VERSION 5.7 ;
  NOWIREEXTENSIONATPIN ON ;
  DIVIDERCHAR "/" ;
  BUSBITCHARS "[]" ;
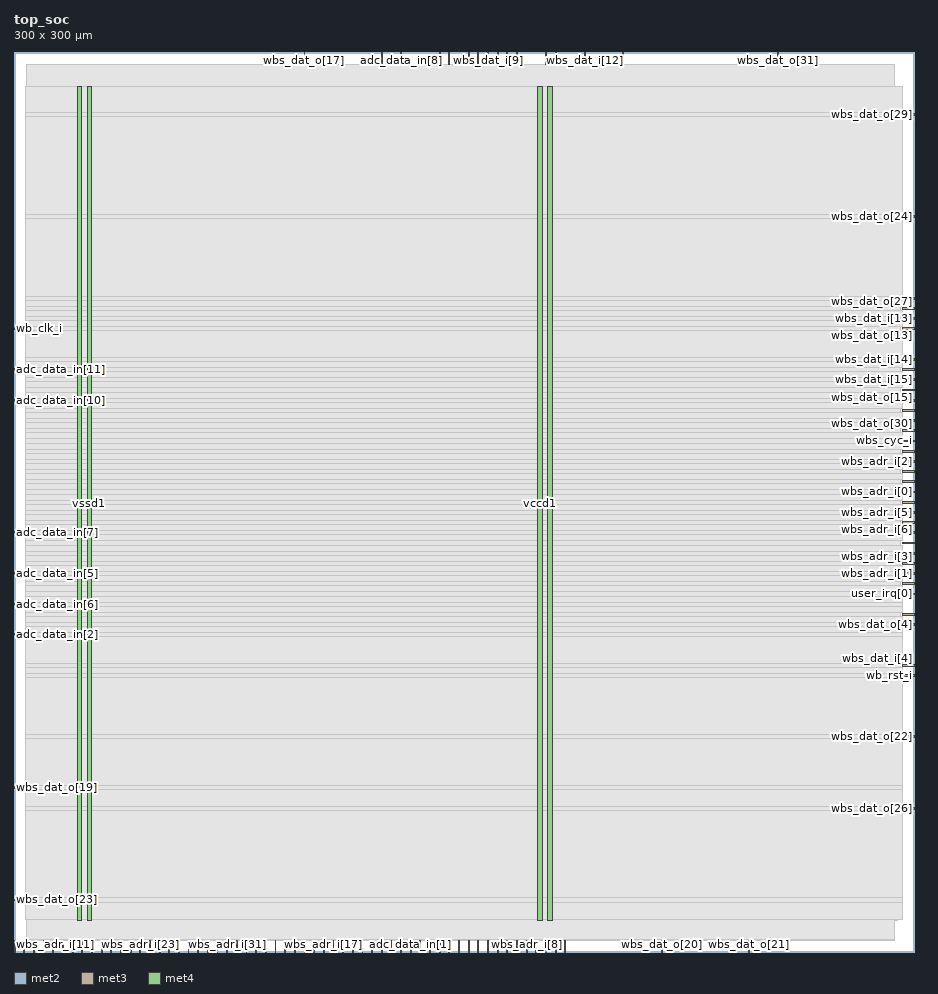
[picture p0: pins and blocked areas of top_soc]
MACRO top_soc
  CLASS BLOCK ;
  FOREIGN top_soc ;
  ORIGIN 0.000 0.000 ;
  SIZE 300.000 BY 300.000 ;
  PIN adc_data_in[0]
    DIRECTION INPUT ;
    USE SIGNAL ;
    ANTENNAGATEAREA 0.631200 ;
    ANTENNADIFFAREA 0.434700 ;
    PORT
      LAYER met2 ;
        RECT 128.890 0.000 129.170 4.000 ;
    END
  END adc_data_in[0]
  PIN adc_data_in[10]
    DIRECTION INPUT ;
    USE SIGNAL ;
    ANTENNAGATEAREA 0.631200 ;
    ANTENNADIFFAREA 0.434700 ;
    PORT
      LAYER met3 ;
        RECT 0.000 183.640 4.000 184.240 ;
    END
  END adc_data_in[10]
  PIN adc_data_in[11]
    DIRECTION INPUT ;
    USE SIGNAL ;
    ANTENNAGATEAREA 0.631200 ;
    ANTENNADIFFAREA 0.434700 ;
    PORT
      LAYER met3 ;
        RECT 0.000 193.840 4.000 194.440 ;
    END
  END adc_data_in[11]
  PIN adc_data_in[1]
    DIRECTION INPUT ;
    USE SIGNAL ;
    ANTENNAGATEAREA 0.631200 ;
    ANTENNADIFFAREA 0.434700 ;
    PORT
      LAYER met2 ;
        RECT 132.110 0.000 132.390 4.000 ;
    END
  END adc_data_in[1]
  PIN adc_data_in[2]
    DIRECTION INPUT ;
    USE SIGNAL ;
    ANTENNAGATEAREA 0.631200 ;
    ANTENNADIFFAREA 0.434700 ;
    PORT
      LAYER met3 ;
        RECT 0.000 105.440 4.000 106.040 ;
    END
  END adc_data_in[2]
  PIN adc_data_in[3]
    DIRECTION INPUT ;
    USE SIGNAL ;
    ANTENNAGATEAREA 0.631200 ;
    ANTENNADIFFAREA 0.434700 ;
    PORT
      LAYER met2 ;
        RECT 93.470 0.000 93.750 4.000 ;
    END
  END adc_data_in[3]
  PIN adc_data_in[4]
    DIRECTION INPUT ;
    USE SIGNAL ;
    ANTENNAGATEAREA 0.631200 ;
    ANTENNADIFFAREA 0.434700 ;
    PORT
      LAYER met2 ;
        RECT 135.330 0.000 135.610 4.000 ;
    END
  END adc_data_in[4]
  PIN adc_data_in[5]
    DIRECTION INPUT ;
    USE SIGNAL ;
    ANTENNAGATEAREA 0.631200 ;
    ANTENNADIFFAREA 0.434700 ;
    PORT
      LAYER met3 ;
        RECT 0.000 125.840 4.000 126.440 ;
    END
  END adc_data_in[5]
  PIN adc_data_in[6]
    DIRECTION INPUT ;
    USE SIGNAL ;
    ANTENNAGATEAREA 0.631200 ;
    ANTENNADIFFAREA 0.434700 ;
    PORT
      LAYER met3 ;
        RECT 0.000 115.640 4.000 116.240 ;
    END
  END adc_data_in[6]
  PIN adc_data_in[7]
    DIRECTION INPUT ;
    USE SIGNAL ;
    ANTENNAGATEAREA 0.631200 ;
    ANTENNADIFFAREA 0.434700 ;
    PORT
      LAYER met3 ;
        RECT 0.000 139.440 4.000 140.040 ;
    END
  END adc_data_in[7]
  PIN adc_data_in[8]
    DIRECTION INPUT ;
    USE SIGNAL ;
    ANTENNAGATEAREA 0.631200 ;
    ANTENNADIFFAREA 0.434700 ;
    PORT
      LAYER met2 ;
        RECT 128.890 296.000 129.170 300.000 ;
    END
  END adc_data_in[8]
  PIN adc_data_in[9]
    DIRECTION INPUT ;
    USE SIGNAL ;
    ANTENNAGATEAREA 0.631200 ;
    ANTENNADIFFAREA 0.434700 ;
    PORT
      LAYER met2 ;
        RECT 122.450 296.000 122.730 300.000 ;
    END
  END adc_data_in[9]
  PIN user_irq[0]
    DIRECTION OUTPUT ;
    USE SIGNAL ;
    ANTENNADIFFAREA 0.445500 ;
    PORT
      LAYER met3 ;
        RECT 296.000 119.040 300.000 119.640 ;
    END
  END user_irq[0]
  PIN user_irq[1]
    DIRECTION OUTPUT ;
    USE SIGNAL ;
    PORT
      LAYER met2 ;
        RECT 125.670 0.000 125.950 4.000 ;
    END
  END user_irq[1]
  PIN user_irq[2]
    DIRECTION OUTPUT ;
    USE SIGNAL ;
    PORT
      LAYER met2 ;
        RECT 67.710 0.000 67.990 4.000 ;
    END
  END user_irq[2]
  PIN vccd1
    DIRECTION INOUT ;
    USE POWER ;
    PORT
      LAYER met4 ;
        RECT 21.040 10.640 22.640 288.560 ;
    END
    PORT
      LAYER met4 ;
        RECT 174.640 10.640 176.240 288.560 ;
    END
  END vccd1
  PIN vssd1
    DIRECTION INOUT ;
    USE GROUND ;
    PORT
      LAYER met4 ;
        RECT 24.340 10.640 25.940 288.560 ;
    END
    PORT
      LAYER met4 ;
        RECT 177.940 10.640 179.540 288.560 ;
    END
  END vssd1
  PIN wb_clk_i
    DIRECTION INPUT ;
    USE SIGNAL ;
    ANTENNAGATEAREA 1.286700 ;
    ANTENNADIFFAREA 0.434700 ;
    PORT
      LAYER met3 ;
        RECT 0.000 207.440 4.000 208.040 ;
    END
  END wb_clk_i
  PIN wb_rst_i
    DIRECTION INPUT ;
    USE SIGNAL ;
    ANTENNAGATEAREA 0.647700 ;
    ANTENNADIFFAREA 0.434700 ;
    PORT
      LAYER met3 ;
        RECT 296.000 91.840 300.000 92.440 ;
    END
  END wb_rst_i
  PIN wbs_ack_o
    DIRECTION OUTPUT ;
    USE SIGNAL ;
    ANTENNADIFFAREA 0.445500 ;
    PORT
      LAYER met3 ;
        RECT 296.000 183.640 300.000 184.240 ;
    END
  END wbs_ack_o
  PIN wbs_adr_i[0]
    DIRECTION INPUT ;
    USE SIGNAL ;
    ANTENNAGATEAREA 0.631200 ;
    ANTENNADIFFAREA 0.434700 ;
    PORT
      LAYER met3 ;
        RECT 296.000 153.040 300.000 153.640 ;
    END
  END wbs_adr_i[0]
  PIN wbs_adr_i[10]
    DIRECTION INPUT ;
    USE SIGNAL ;
    PORT
      LAYER met2 ;
        RECT 87.030 0.000 87.310 4.000 ;
    END
  END wbs_adr_i[10]
  PIN wbs_adr_i[11]
    DIRECTION INPUT ;
    USE SIGNAL ;
    PORT
      LAYER met2 ;
        RECT 9.750 0.000 10.030 4.000 ;
    END
  END wbs_adr_i[11]
  PIN wbs_adr_i[12]
    DIRECTION INPUT ;
    USE SIGNAL ;
    PORT
      LAYER met2 ;
        RECT 12.970 0.000 13.250 4.000 ;
    END
  END wbs_adr_i[12]
  PIN wbs_adr_i[13]
    DIRECTION INPUT ;
    USE SIGNAL ;
    PORT
      LAYER met2 ;
        RECT 16.190 0.000 16.470 4.000 ;
    END
  END wbs_adr_i[13]
  PIN wbs_adr_i[14]
    DIRECTION INPUT ;
    USE SIGNAL ;
    PORT
      LAYER met2 ;
        RECT 19.410 0.000 19.690 4.000 ;
    END
  END wbs_adr_i[14]
  PIN wbs_adr_i[15]
    DIRECTION INPUT ;
    USE SIGNAL ;
    PORT
      LAYER met2 ;
        RECT 22.630 0.000 22.910 4.000 ;
    END
  END wbs_adr_i[15]
  PIN wbs_adr_i[16]
    DIRECTION INPUT ;
    USE SIGNAL ;
    PORT
      LAYER met2 ;
        RECT 25.850 0.000 26.130 4.000 ;
    END
  END wbs_adr_i[16]
  PIN wbs_adr_i[17]
    DIRECTION INPUT ;
    USE SIGNAL ;
    PORT
      LAYER met2 ;
        RECT 103.130 0.000 103.410 4.000 ;
    END
  END wbs_adr_i[17]
  PIN wbs_adr_i[18]
    DIRECTION INPUT ;
    USE SIGNAL ;
    PORT
      LAYER met2 ;
        RECT 99.910 0.000 100.190 4.000 ;
    END
  END wbs_adr_i[18]
  PIN wbs_adr_i[19]
    DIRECTION INPUT ;
    USE SIGNAL ;
    PORT
      LAYER met2 ;
        RECT 29.070 0.000 29.350 4.000 ;
    END
  END wbs_adr_i[19]
  PIN wbs_adr_i[1]
    DIRECTION INPUT ;
    USE SIGNAL ;
    ANTENNAGATEAREA 0.631200 ;
    ANTENNADIFFAREA 0.434700 ;
    PORT
      LAYER met3 ;
        RECT 296.000 125.840 300.000 126.440 ;
    END
  END wbs_adr_i[1]
  PIN wbs_adr_i[20]
    DIRECTION INPUT ;
    USE SIGNAL ;
    PORT
      LAYER met2 ;
        RECT 32.290 0.000 32.570 4.000 ;
    END
  END wbs_adr_i[20]
  PIN wbs_adr_i[21]
    DIRECTION INPUT ;
    USE SIGNAL ;
    PORT
      LAYER met2 ;
        RECT 35.510 0.000 35.790 4.000 ;
    END
  END wbs_adr_i[21]
  PIN wbs_adr_i[22]
    DIRECTION INPUT ;
    USE SIGNAL ;
    PORT
      LAYER met2 ;
        RECT 38.730 0.000 39.010 4.000 ;
    END
  END wbs_adr_i[22]
  PIN wbs_adr_i[23]
    DIRECTION INPUT ;
    USE SIGNAL ;
    PORT
      LAYER met2 ;
        RECT 41.950 0.000 42.230 4.000 ;
    END
  END wbs_adr_i[23]
  PIN wbs_adr_i[24]
    DIRECTION INPUT ;
    USE SIGNAL ;
    PORT
      LAYER met2 ;
        RECT 45.170 0.000 45.450 4.000 ;
    END
  END wbs_adr_i[24]
  PIN wbs_adr_i[25]
    DIRECTION INPUT ;
    USE SIGNAL ;
    PORT
      LAYER met2 ;
        RECT 48.390 0.000 48.670 4.000 ;
    END
  END wbs_adr_i[25]
  PIN wbs_adr_i[26]
    DIRECTION INPUT ;
    USE SIGNAL ;
    PORT
      LAYER met2 ;
        RECT 51.610 0.000 51.890 4.000 ;
    END
  END wbs_adr_i[26]
  PIN wbs_adr_i[27]
    DIRECTION INPUT ;
    USE SIGNAL ;
    PORT
      LAYER met2 ;
        RECT 54.830 0.000 55.110 4.000 ;
    END
  END wbs_adr_i[27]
  PIN wbs_adr_i[28]
    DIRECTION INPUT ;
    USE SIGNAL ;
    PORT
      LAYER met2 ;
        RECT 58.050 0.000 58.330 4.000 ;
    END
  END wbs_adr_i[28]
  PIN wbs_adr_i[29]
    DIRECTION INPUT ;
    USE SIGNAL ;
    PORT
      LAYER met2 ;
        RECT 61.270 0.000 61.550 4.000 ;
    END
  END wbs_adr_i[29]
  PIN wbs_adr_i[2]
    DIRECTION INPUT ;
    USE SIGNAL ;
    ANTENNAGATEAREA 0.647700 ;
    ANTENNADIFFAREA 0.434700 ;
    PORT
      LAYER met3 ;
        RECT 296.000 163.240 300.000 163.840 ;
    END
  END wbs_adr_i[2]
  PIN wbs_adr_i[30]
    DIRECTION INPUT ;
    USE SIGNAL ;
    PORT
      LAYER met2 ;
        RECT 64.490 0.000 64.770 4.000 ;
    END
  END wbs_adr_i[30]
  PIN wbs_adr_i[31]
    DIRECTION INPUT ;
    USE SIGNAL ;
    PORT
      LAYER met2 ;
        RECT 70.930 0.000 71.210 4.000 ;
    END
  END wbs_adr_i[31]
  PIN wbs_adr_i[3]
    DIRECTION INPUT ;
    USE SIGNAL ;
    ANTENNAGATEAREA 0.631200 ;
    ANTENNADIFFAREA 0.434700 ;
    PORT
      LAYER met3 ;
        RECT 296.000 129.240 300.000 129.840 ;
    END
  END wbs_adr_i[3]
  PIN wbs_adr_i[4]
    DIRECTION INPUT ;
    USE SIGNAL ;
    ANTENNAGATEAREA 0.631200 ;
    ANTENNADIFFAREA 0.434700 ;
    PORT
      LAYER met3 ;
        RECT 296.000 159.840 300.000 160.440 ;
    END
  END wbs_adr_i[4]
  PIN wbs_adr_i[5]
    DIRECTION INPUT ;
    USE SIGNAL ;
    ANTENNAGATEAREA 0.631200 ;
    ANTENNADIFFAREA 0.434700 ;
    PORT
      LAYER met3 ;
        RECT 296.000 146.240 300.000 146.840 ;
    END
  END wbs_adr_i[5]
  PIN wbs_adr_i[6]
    DIRECTION INPUT ;
    USE SIGNAL ;
    ANTENNAGATEAREA 0.631200 ;
    ANTENNADIFFAREA 0.434700 ;
    PORT
      LAYER met3 ;
        RECT 296.000 142.840 300.000 143.440 ;
    END
  END wbs_adr_i[6]
  PIN wbs_adr_i[7]
    DIRECTION INPUT ;
    USE SIGNAL ;
    ANTENNAGATEAREA 0.631200 ;
    ANTENNADIFFAREA 0.434700 ;
    PORT
      LAYER met3 ;
        RECT 296.000 156.440 300.000 157.040 ;
    END
  END wbs_adr_i[7]
  PIN wbs_adr_i[8]
    DIRECTION INPUT ;
    USE SIGNAL ;
    PORT
      LAYER met2 ;
        RECT 170.750 0.000 171.030 4.000 ;
    END
  END wbs_adr_i[8]
  PIN wbs_adr_i[9]
    DIRECTION INPUT ;
    USE SIGNAL ;
    PORT
      LAYER met2 ;
        RECT 77.370 0.000 77.650 4.000 ;
    END
  END wbs_adr_i[9]
  PIN wbs_cyc_i
    DIRECTION INPUT ;
    USE SIGNAL ;
    ANTENNAGATEAREA 0.631200 ;
    ANTENNADIFFAREA 0.434700 ;
    PORT
      LAYER met3 ;
        RECT 296.000 170.040 300.000 170.640 ;
    END
  END wbs_cyc_i
  PIN wbs_dat_i[0]
    DIRECTION INPUT ;
    USE SIGNAL ;
    ANTENNAGATEAREA 0.631200 ;
    ANTENNADIFFAREA 0.434700 ;
    PORT
      LAYER met3 ;
        RECT 296.000 166.640 300.000 167.240 ;
    END
  END wbs_dat_i[0]
  PIN wbs_dat_i[10]
    DIRECTION INPUT ;
    USE SIGNAL ;
    ANTENNAGATEAREA 0.631200 ;
    ANTENNADIFFAREA 0.434700 ;
    PORT
      LAYER met2 ;
        RECT 141.770 296.000 142.050 300.000 ;
    END
  END wbs_dat_i[10]
  PIN wbs_dat_i[11]
    DIRECTION INPUT ;
    USE SIGNAL ;
    ANTENNAGATEAREA 0.631200 ;
    ANTENNADIFFAREA 0.434700 ;
    PORT
      LAYER met2 ;
        RECT 151.430 296.000 151.710 300.000 ;
    END
  END wbs_dat_i[11]
  PIN wbs_dat_i[12]
    DIRECTION INPUT ;
    USE SIGNAL ;
    ANTENNAGATEAREA 0.631200 ;
    ANTENNADIFFAREA 0.434700 ;
    PORT
      LAYER met2 ;
        RECT 190.070 296.000 190.350 300.000 ;
    END
  END wbs_dat_i[12]
  PIN wbs_dat_i[13]
    DIRECTION INPUT ;
    USE SIGNAL ;
    ANTENNAGATEAREA 0.631200 ;
    ANTENNADIFFAREA 0.434700 ;
    PORT
      LAYER met3 ;
        RECT 296.000 210.840 300.000 211.440 ;
    END
  END wbs_dat_i[13]
  PIN wbs_dat_i[14]
    DIRECTION INPUT ;
    USE SIGNAL ;
    ANTENNAGATEAREA 0.631200 ;
    ANTENNADIFFAREA 0.434700 ;
    PORT
      LAYER met3 ;
        RECT 296.000 197.240 300.000 197.840 ;
    END
  END wbs_dat_i[14]
  PIN wbs_dat_i[15]
    DIRECTION INPUT ;
    USE SIGNAL ;
    ANTENNAGATEAREA 0.631200 ;
    ANTENNADIFFAREA 0.434700 ;
    PORT
      LAYER met3 ;
        RECT 296.000 190.440 300.000 191.040 ;
    END
  END wbs_dat_i[15]
  PIN wbs_dat_i[16]
    DIRECTION INPUT ;
    USE SIGNAL ;
    PORT
      LAYER met2 ;
        RECT 80.590 0.000 80.870 4.000 ;
    END
  END wbs_dat_i[16]
  PIN wbs_dat_i[17]
    DIRECTION INPUT ;
    USE SIGNAL ;
    PORT
      LAYER met2 ;
        RECT 83.810 0.000 84.090 4.000 ;
    END
  END wbs_dat_i[17]
  PIN wbs_dat_i[18]
    DIRECTION INPUT ;
    USE SIGNAL ;
    PORT
      LAYER met2 ;
        RECT 177.190 0.000 177.470 4.000 ;
    END
  END wbs_dat_i[18]
  PIN wbs_dat_i[19]
    DIRECTION INPUT ;
    USE SIGNAL ;
    PORT
      LAYER met2 ;
        RECT 90.250 0.000 90.530 4.000 ;
    END
  END wbs_dat_i[19]
  PIN wbs_dat_i[1]
    DIRECTION INPUT ;
    USE SIGNAL ;
    ANTENNAGATEAREA 0.560700 ;
    ANTENNADIFFAREA 0.434700 ;
    PORT
      LAYER met2 ;
        RECT 154.650 0.000 154.930 4.000 ;
    END
  END wbs_dat_i[1]
  PIN wbs_dat_i[20]
    DIRECTION INPUT ;
    USE SIGNAL ;
    PORT
      LAYER met2 ;
        RECT 96.690 0.000 96.970 4.000 ;
    END
  END wbs_dat_i[20]
  PIN wbs_dat_i[21]
    DIRECTION INPUT ;
    USE SIGNAL ;
    PORT
      LAYER met2 ;
        RECT 173.970 0.000 174.250 4.000 ;
    END
  END wbs_dat_i[21]
  PIN wbs_dat_i[22]
    DIRECTION INPUT ;
    USE SIGNAL ;
    PORT
      LAYER met2 ;
        RECT 183.630 0.000 183.910 4.000 ;
    END
  END wbs_dat_i[22]
  PIN wbs_dat_i[23]
    DIRECTION INPUT ;
    USE SIGNAL ;
    PORT
      LAYER met2 ;
        RECT 106.350 0.000 106.630 4.000 ;
    END
  END wbs_dat_i[23]
  PIN wbs_dat_i[24]
    DIRECTION INPUT ;
    USE SIGNAL ;
    PORT
      LAYER met2 ;
        RECT 109.570 0.000 109.850 4.000 ;
    END
  END wbs_dat_i[24]
  PIN wbs_dat_i[25]
    DIRECTION INPUT ;
    USE SIGNAL ;
    PORT
      LAYER met2 ;
        RECT 112.790 0.000 113.070 4.000 ;
    END
  END wbs_dat_i[25]
  PIN wbs_dat_i[26]
    DIRECTION INPUT ;
    USE SIGNAL ;
    PORT
      LAYER met2 ;
        RECT 116.010 0.000 116.290 4.000 ;
    END
  END wbs_dat_i[26]
  PIN wbs_dat_i[27]
    DIRECTION INPUT ;
    USE SIGNAL ;
    PORT
      LAYER met2 ;
        RECT 119.230 0.000 119.510 4.000 ;
    END
  END wbs_dat_i[27]
  PIN wbs_dat_i[28]
    DIRECTION INPUT ;
    USE SIGNAL ;
    PORT
      LAYER met2 ;
        RECT 3.310 0.000 3.590 4.000 ;
    END
  END wbs_dat_i[28]
  PIN wbs_dat_i[29]
    DIRECTION INPUT ;
    USE SIGNAL ;
    PORT
      LAYER met2 ;
        RECT 0.090 0.000 0.370 4.000 ;
    END
  END wbs_dat_i[29]
  PIN wbs_dat_i[2]
    DIRECTION INPUT ;
    USE SIGNAL ;
    ANTENNAGATEAREA 0.647700 ;
    ANTENNADIFFAREA 0.434700 ;
    PORT
      LAYER met2 ;
        RECT 164.310 296.000 164.590 300.000 ;
    END
  END wbs_dat_i[2]
  PIN wbs_dat_i[30]
    DIRECTION INPUT ;
    USE SIGNAL ;
    PORT
      LAYER met2 ;
        RECT 6.530 0.000 6.810 4.000 ;
    END
  END wbs_dat_i[30]
  PIN wbs_dat_i[31]
    DIRECTION INPUT ;
    USE SIGNAL ;
    PORT
      LAYER met2 ;
        RECT 138.550 0.000 138.830 4.000 ;
    END
  END wbs_dat_i[31]
  PIN wbs_dat_i[3]
    DIRECTION INPUT ;
    USE SIGNAL ;
    ANTENNAGATEAREA 0.560700 ;
    ANTENNADIFFAREA 0.434700 ;
    PORT
      LAYER met2 ;
        RECT 164.310 0.000 164.590 4.000 ;
    END
  END wbs_dat_i[3]
  PIN wbs_dat_i[4]
    DIRECTION INPUT ;
    USE SIGNAL ;
    ANTENNAGATEAREA 0.631200 ;
    ANTENNADIFFAREA 0.434700 ;
    PORT
      LAYER met3 ;
        RECT 296.000 95.240 300.000 95.840 ;
    END
  END wbs_dat_i[4]
  PIN wbs_dat_i[5]
    DIRECTION INPUT ;
    USE SIGNAL ;
    ANTENNAGATEAREA 0.647700 ;
    ANTENNADIFFAREA 0.434700 ;
    PORT
      LAYER met2 ;
        RECT 180.410 0.000 180.690 4.000 ;
    END
  END wbs_dat_i[5]
  PIN wbs_dat_i[6]
    DIRECTION INPUT ;
    USE SIGNAL ;
    ANTENNAGATEAREA 0.647700 ;
    ANTENNADIFFAREA 0.434700 ;
    PORT
      LAYER met2 ;
        RECT 157.870 0.000 158.150 4.000 ;
    END
  END wbs_dat_i[6]
  PIN wbs_dat_i[7]
    DIRECTION INPUT ;
    USE SIGNAL ;
    ANTENNAGATEAREA 0.631200 ;
    ANTENNADIFFAREA 0.434700 ;
    PORT
      LAYER met3 ;
        RECT 296.000 122.440 300.000 123.040 ;
    END
  END wbs_dat_i[7]
  PIN wbs_dat_i[8]
    DIRECTION INPUT ;
    USE SIGNAL ;
    ANTENNAGATEAREA 0.631200 ;
    ANTENNADIFFAREA 0.434700 ;
    PORT
      LAYER met2 ;
        RECT 177.190 296.000 177.470 300.000 ;
    END
  END wbs_dat_i[8]
  PIN wbs_dat_i[9]
    DIRECTION INPUT ;
    USE SIGNAL ;
    ANTENNAGATEAREA 0.631200 ;
    ANTENNADIFFAREA 0.434700 ;
    PORT
      LAYER met2 ;
        RECT 157.870 296.000 158.150 300.000 ;
    END
  END wbs_dat_i[9]
  PIN wbs_dat_o[0]
    DIRECTION OUTPUT ;
    USE SIGNAL ;
    ANTENNADIFFAREA 0.445500 ;
    PORT
      LAYER met3 ;
        RECT 296.000 136.040 300.000 136.640 ;
    END
  END wbs_dat_o[0]
  PIN wbs_dat_o[10]
    DIRECTION OUTPUT ;
    USE SIGNAL ;
    ANTENNADIFFAREA 0.445500 ;
    PORT
      LAYER met2 ;
        RECT 144.990 296.000 145.270 300.000 ;
    END
  END wbs_dat_o[10]
  PIN wbs_dat_o[11]
    DIRECTION OUTPUT ;
    USE SIGNAL ;
    ANTENNADIFFAREA 0.445500 ;
    PORT
      LAYER met2 ;
        RECT 154.650 296.000 154.930 300.000 ;
    END
  END wbs_dat_o[11]
  PIN wbs_dat_o[12]
    DIRECTION OUTPUT ;
    USE SIGNAL ;
    ANTENNADIFFAREA 0.445500 ;
    PORT
      LAYER met2 ;
        RECT 202.950 296.000 203.230 300.000 ;
    END
  END wbs_dat_o[12]
  PIN wbs_dat_o[13]
    DIRECTION OUTPUT ;
    USE SIGNAL ;
    ANTENNADIFFAREA 0.445500 ;
    PORT
      LAYER met3 ;
        RECT 296.000 207.440 300.000 208.040 ;
    END
  END wbs_dat_o[13]
  PIN wbs_dat_o[14]
    DIRECTION OUTPUT ;
    USE SIGNAL ;
    ANTENNADIFFAREA 0.445500 ;
    PORT
      LAYER met3 ;
        RECT 296.000 193.840 300.000 194.440 ;
    END
  END wbs_dat_o[14]
  PIN wbs_dat_o[15]
    DIRECTION OUTPUT ;
    USE SIGNAL ;
    ANTENNADIFFAREA 0.445500 ;
    PORT
      LAYER met3 ;
        RECT 296.000 187.040 300.000 187.640 ;
    END
  END wbs_dat_o[15]
  PIN wbs_dat_o[16]
    DIRECTION OUTPUT ;
    USE SIGNAL ;
    PORT
      LAYER met3 ;
        RECT 296.000 217.640 300.000 218.240 ;
    END
  END wbs_dat_o[16]
  PIN wbs_dat_o[17]
    DIRECTION OUTPUT ;
    USE SIGNAL ;
    PORT
      LAYER met2 ;
        RECT 96.690 296.000 96.970 300.000 ;
    END
  END wbs_dat_o[17]
  PIN wbs_dat_o[18]
    DIRECTION OUTPUT ;
    USE SIGNAL ;
    PORT
      LAYER met2 ;
        RECT 122.450 0.000 122.730 4.000 ;
    END
  END wbs_dat_o[18]
  PIN wbs_dat_o[19]
    DIRECTION OUTPUT ;
    USE SIGNAL ;
    PORT
      LAYER met3 ;
        RECT 0.000 54.440 4.000 55.040 ;
    END
  END wbs_dat_o[19]
  PIN wbs_dat_o[1]
    DIRECTION OUTPUT ;
    USE SIGNAL ;
    ANTENNADIFFAREA 0.445500 ;
    PORT
      LAYER met2 ;
        RECT 141.770 0.000 142.050 4.000 ;
    END
  END wbs_dat_o[1]
  PIN wbs_dat_o[20]
    DIRECTION OUTPUT ;
    USE SIGNAL ;
    PORT
      LAYER met2 ;
        RECT 215.830 0.000 216.110 4.000 ;
    END
  END wbs_dat_o[20]
  PIN wbs_dat_o[21]
    DIRECTION OUTPUT ;
    USE SIGNAL ;
    PORT
      LAYER met2 ;
        RECT 244.810 0.000 245.090 4.000 ;
    END
  END wbs_dat_o[21]
  PIN wbs_dat_o[22]
    DIRECTION OUTPUT ;
    USE SIGNAL ;
    PORT
      LAYER met3 ;
        RECT 296.000 71.440 300.000 72.040 ;
    END
  END wbs_dat_o[22]
  PIN wbs_dat_o[23]
    DIRECTION OUTPUT ;
    USE SIGNAL ;
    PORT
      LAYER met3 ;
        RECT 0.000 17.040 4.000 17.640 ;
    END
  END wbs_dat_o[23]
  PIN wbs_dat_o[24]
    DIRECTION OUTPUT ;
    USE SIGNAL ;
    PORT
      LAYER met3 ;
        RECT 296.000 244.840 300.000 245.440 ;
    END
  END wbs_dat_o[24]
  PIN wbs_dat_o[25]
    DIRECTION OUTPUT ;
    USE SIGNAL ;
    PORT
      LAYER met3 ;
        RECT 296.000 139.440 300.000 140.040 ;
    END
  END wbs_dat_o[25]
  PIN wbs_dat_o[26]
    DIRECTION OUTPUT ;
    USE SIGNAL ;
    PORT
      LAYER met3 ;
        RECT 296.000 47.640 300.000 48.240 ;
    END
  END wbs_dat_o[26]
  PIN wbs_dat_o[27]
    DIRECTION OUTPUT ;
    USE SIGNAL ;
    PORT
      LAYER met3 ;
        RECT 296.000 214.240 300.000 214.840 ;
    END
  END wbs_dat_o[27]
  PIN wbs_dat_o[28]
    DIRECTION OUTPUT ;
    USE SIGNAL ;
    PORT
      LAYER met2 ;
        RECT 167.530 296.000 167.810 300.000 ;
    END
  END wbs_dat_o[28]
  PIN wbs_dat_o[29]
    DIRECTION OUTPUT ;
    USE SIGNAL ;
    PORT
      LAYER met3 ;
        RECT 296.000 278.840 300.000 279.440 ;
    END
  END wbs_dat_o[29]
  PIN wbs_dat_o[2]
    DIRECTION OUTPUT ;
    USE SIGNAL ;
    ANTENNADIFFAREA 0.445500 ;
    PORT
      LAYER met3 ;
        RECT 296.000 149.640 300.000 150.240 ;
    END
  END wbs_dat_o[2]
  PIN wbs_dat_o[30]
    DIRECTION OUTPUT ;
    USE SIGNAL ;
    PORT
      LAYER met3 ;
        RECT 296.000 173.440 300.000 174.040 ;
    END
  END wbs_dat_o[30]
  PIN wbs_dat_o[31]
    DIRECTION OUTPUT ;
    USE SIGNAL ;
    PORT
      LAYER met2 ;
        RECT 254.470 296.000 254.750 300.000 ;
    END
  END wbs_dat_o[31]
  PIN wbs_dat_o[3]
    DIRECTION OUTPUT ;
    USE SIGNAL ;
    ANTENNADIFFAREA 0.445500 ;
    PORT
      LAYER met2 ;
        RECT 167.530 0.000 167.810 4.000 ;
    END
  END wbs_dat_o[3]
  PIN wbs_dat_o[4]
    DIRECTION OUTPUT ;
    USE SIGNAL ;
    ANTENNADIFFAREA 0.445500 ;
    PORT
      LAYER met3 ;
        RECT 296.000 108.840 300.000 109.440 ;
    END
  END wbs_dat_o[4]
  PIN wbs_dat_o[5]
    DIRECTION OUTPUT ;
    USE SIGNAL ;
    ANTENNADIFFAREA 0.445500 ;
    PORT
      LAYER met3 ;
        RECT 296.000 112.240 300.000 112.840 ;
    END
  END wbs_dat_o[5]
  PIN wbs_dat_o[6]
    DIRECTION OUTPUT ;
    USE SIGNAL ;
    ANTENNADIFFAREA 0.445500 ;
    PORT
      LAYER met2 ;
        RECT 151.430 0.000 151.710 4.000 ;
    END
  END wbs_dat_o[6]
  PIN wbs_dat_o[7]
    DIRECTION OUTPUT ;
    USE SIGNAL ;
    ANTENNADIFFAREA 0.445500 ;
    PORT
      LAYER met3 ;
        RECT 296.000 132.640 300.000 133.240 ;
    END
  END wbs_dat_o[7]
  PIN wbs_dat_o[8]
    DIRECTION OUTPUT ;
    USE SIGNAL ;
    ANTENNADIFFAREA 0.445500 ;
    PORT
      LAYER met2 ;
        RECT 180.410 296.000 180.690 300.000 ;
    END
  END wbs_dat_o[8]
  PIN wbs_dat_o[9]
    DIRECTION OUTPUT ;
    USE SIGNAL ;
    ANTENNADIFFAREA 0.445500 ;
    PORT
      LAYER met2 ;
        RECT 161.090 296.000 161.370 300.000 ;
    END
  END wbs_dat_o[9]
  PIN wbs_sel_i[0]
    DIRECTION INPUT ;
    USE SIGNAL ;
    PORT
      LAYER met2 ;
        RECT 144.990 0.000 145.270 4.000 ;
    END
  END wbs_sel_i[0]
  PIN wbs_sel_i[1]
    DIRECTION INPUT ;
    USE SIGNAL ;
    PORT
      LAYER met2 ;
        RECT 148.210 0.000 148.490 4.000 ;
    END
  END wbs_sel_i[1]
  PIN wbs_sel_i[2]
    DIRECTION INPUT ;
    USE SIGNAL ;
    PORT
      LAYER met2 ;
        RECT 161.090 0.000 161.370 4.000 ;
    END
  END wbs_sel_i[2]
  PIN wbs_sel_i[3]
    DIRECTION INPUT ;
    USE SIGNAL ;
    PORT
      LAYER met2 ;
        RECT 74.150 0.000 74.430 4.000 ;
    END
  END wbs_sel_i[3]
  PIN wbs_stb_i
    DIRECTION INPUT ;
    USE SIGNAL ;
    ANTENNAGATEAREA 0.631200 ;
    ANTENNADIFFAREA 0.434700 ;
    PORT
      LAYER met3 ;
        RECT 296.000 176.840 300.000 177.440 ;
    END
  END wbs_stb_i
  PIN wbs_we_i
    DIRECTION INPUT ;
    USE SIGNAL ;
    ANTENNAGATEAREA 0.647700 ;
    ANTENNADIFFAREA 0.434700 ;
    PORT
      LAYER met3 ;
        RECT 296.000 180.240 300.000 180.840 ;
    END
  END wbs_we_i
  OBS
      LAYER nwell ;
        RECT 5.330 10.760 294.590 288.440 ;
      LAYER li1 ;
        RECT 5.520 10.795 294.400 288.405 ;
      LAYER met1 ;
        RECT 4.210 10.640 294.400 288.560 ;
      LAYER met2 ;
        RECT 4.230 295.720 96.410 296.000 ;
        RECT 97.250 295.720 122.170 296.000 ;
        RECT 123.010 295.720 128.610 296.000 ;
        RECT 129.450 295.720 141.490 296.000 ;
        RECT 142.330 295.720 144.710 296.000 ;
        RECT 145.550 295.720 151.150 296.000 ;
        RECT 151.990 295.720 154.370 296.000 ;
        RECT 155.210 295.720 157.590 296.000 ;
        RECT 158.430 295.720 160.810 296.000 ;
        RECT 161.650 295.720 164.030 296.000 ;
        RECT 164.870 295.720 167.250 296.000 ;
        RECT 168.090 295.720 176.910 296.000 ;
        RECT 177.750 295.720 180.130 296.000 ;
        RECT 180.970 295.720 189.790 296.000 ;
        RECT 190.630 295.720 202.670 296.000 ;
        RECT 203.510 295.720 254.190 296.000 ;
        RECT 255.030 295.720 293.380 296.000 ;
        RECT 4.230 4.280 293.380 295.720 ;
        RECT 4.230 4.000 6.250 4.280 ;
        RECT 7.090 4.000 9.470 4.280 ;
        RECT 10.310 4.000 12.690 4.280 ;
        RECT 13.530 4.000 15.910 4.280 ;
        RECT 16.750 4.000 19.130 4.280 ;
        RECT 19.970 4.000 22.350 4.280 ;
        RECT 23.190 4.000 25.570 4.280 ;
        RECT 26.410 4.000 28.790 4.280 ;
        RECT 29.630 4.000 32.010 4.280 ;
        RECT 32.850 4.000 35.230 4.280 ;
        RECT 36.070 4.000 38.450 4.280 ;
        RECT 39.290 4.000 41.670 4.280 ;
        RECT 42.510 4.000 44.890 4.280 ;
        RECT 45.730 4.000 48.110 4.280 ;
        RECT 48.950 4.000 51.330 4.280 ;
        RECT 52.170 4.000 54.550 4.280 ;
        RECT 55.390 4.000 57.770 4.280 ;
        RECT 58.610 4.000 60.990 4.280 ;
        RECT 61.830 4.000 64.210 4.280 ;
        RECT 65.050 4.000 67.430 4.280 ;
        RECT 68.270 4.000 70.650 4.280 ;
        RECT 71.490 4.000 73.870 4.280 ;
        RECT 74.710 4.000 77.090 4.280 ;
        RECT 77.930 4.000 80.310 4.280 ;
        RECT 81.150 4.000 83.530 4.280 ;
        RECT 84.370 4.000 86.750 4.280 ;
        RECT 87.590 4.000 89.970 4.280 ;
        RECT 90.810 4.000 93.190 4.280 ;
        RECT 94.030 4.000 96.410 4.280 ;
        RECT 97.250 4.000 99.630 4.280 ;
        RECT 100.470 4.000 102.850 4.280 ;
        RECT 103.690 4.000 106.070 4.280 ;
        RECT 106.910 4.000 109.290 4.280 ;
        RECT 110.130 4.000 112.510 4.280 ;
        RECT 113.350 4.000 115.730 4.280 ;
        RECT 116.570 4.000 118.950 4.280 ;
        RECT 119.790 4.000 122.170 4.280 ;
        RECT 123.010 4.000 125.390 4.280 ;
        RECT 126.230 4.000 128.610 4.280 ;
        RECT 129.450 4.000 131.830 4.280 ;
        RECT 132.670 4.000 135.050 4.280 ;
        RECT 135.890 4.000 138.270 4.280 ;
        RECT 139.110 4.000 141.490 4.280 ;
        RECT 142.330 4.000 144.710 4.280 ;
        RECT 145.550 4.000 147.930 4.280 ;
        RECT 148.770 4.000 151.150 4.280 ;
        RECT 151.990 4.000 154.370 4.280 ;
        RECT 155.210 4.000 157.590 4.280 ;
        RECT 158.430 4.000 160.810 4.280 ;
        RECT 161.650 4.000 164.030 4.280 ;
        RECT 164.870 4.000 167.250 4.280 ;
        RECT 168.090 4.000 170.470 4.280 ;
        RECT 171.310 4.000 173.690 4.280 ;
        RECT 174.530 4.000 176.910 4.280 ;
        RECT 177.750 4.000 180.130 4.280 ;
        RECT 180.970 4.000 183.350 4.280 ;
        RECT 184.190 4.000 215.550 4.280 ;
        RECT 216.390 4.000 244.530 4.280 ;
        RECT 245.370 4.000 293.380 4.280 ;
      LAYER met3 ;
        RECT 3.990 279.840 296.000 288.485 ;
        RECT 3.990 278.440 295.600 279.840 ;
        RECT 3.990 245.840 296.000 278.440 ;
        RECT 3.990 244.440 295.600 245.840 ;
        RECT 3.990 218.640 296.000 244.440 ;
        RECT 3.990 217.240 295.600 218.640 ;
        RECT 3.990 215.240 296.000 217.240 ;
        RECT 3.990 213.840 295.600 215.240 ;
        RECT 3.990 211.840 296.000 213.840 ;
        RECT 3.990 210.440 295.600 211.840 ;
        RECT 3.990 208.440 296.000 210.440 ;
        RECT 4.400 207.040 295.600 208.440 ;
        RECT 3.990 198.240 296.000 207.040 ;
        RECT 3.990 196.840 295.600 198.240 ;
        RECT 3.990 194.840 296.000 196.840 ;
        RECT 4.400 193.440 295.600 194.840 ;
        RECT 3.990 191.440 296.000 193.440 ;
        RECT 3.990 190.040 295.600 191.440 ;
        RECT 3.990 188.040 296.000 190.040 ;
        RECT 3.990 186.640 295.600 188.040 ;
        RECT 3.990 184.640 296.000 186.640 ;
        RECT 4.400 183.240 295.600 184.640 ;
        RECT 3.990 181.240 296.000 183.240 ;
        RECT 3.990 179.840 295.600 181.240 ;
        RECT 3.990 177.840 296.000 179.840 ;
        RECT 3.990 176.440 295.600 177.840 ;
        RECT 3.990 174.440 296.000 176.440 ;
        RECT 3.990 173.040 295.600 174.440 ;
        RECT 3.990 171.040 296.000 173.040 ;
        RECT 3.990 169.640 295.600 171.040 ;
        RECT 3.990 167.640 296.000 169.640 ;
        RECT 3.990 166.240 295.600 167.640 ;
        RECT 3.990 164.240 296.000 166.240 ;
        RECT 3.990 162.840 295.600 164.240 ;
        RECT 3.990 160.840 296.000 162.840 ;
        RECT 3.990 159.440 295.600 160.840 ;
        RECT 3.990 157.440 296.000 159.440 ;
        RECT 3.990 156.040 295.600 157.440 ;
        RECT 3.990 154.040 296.000 156.040 ;
        RECT 3.990 152.640 295.600 154.040 ;
        RECT 3.990 150.640 296.000 152.640 ;
        RECT 3.990 149.240 295.600 150.640 ;
        RECT 3.990 147.240 296.000 149.240 ;
        RECT 3.990 145.840 295.600 147.240 ;
        RECT 3.990 143.840 296.000 145.840 ;
        RECT 3.990 142.440 295.600 143.840 ;
        RECT 3.990 140.440 296.000 142.440 ;
        RECT 4.400 139.040 295.600 140.440 ;
        RECT 3.990 137.040 296.000 139.040 ;
        RECT 3.990 135.640 295.600 137.040 ;
        RECT 3.990 133.640 296.000 135.640 ;
        RECT 3.990 132.240 295.600 133.640 ;
        RECT 3.990 130.240 296.000 132.240 ;
        RECT 3.990 128.840 295.600 130.240 ;
        RECT 3.990 126.840 296.000 128.840 ;
        RECT 4.400 125.440 295.600 126.840 ;
        RECT 3.990 123.440 296.000 125.440 ;
        RECT 3.990 122.040 295.600 123.440 ;
        RECT 3.990 120.040 296.000 122.040 ;
        RECT 3.990 118.640 295.600 120.040 ;
        RECT 3.990 116.640 296.000 118.640 ;
        RECT 4.400 115.240 296.000 116.640 ;
        RECT 3.990 113.240 296.000 115.240 ;
        RECT 3.990 111.840 295.600 113.240 ;
        RECT 3.990 109.840 296.000 111.840 ;
        RECT 3.990 108.440 295.600 109.840 ;
        RECT 3.990 106.440 296.000 108.440 ;
        RECT 4.400 105.040 296.000 106.440 ;
        RECT 3.990 96.240 296.000 105.040 ;
        RECT 3.990 94.840 295.600 96.240 ;
        RECT 3.990 92.840 296.000 94.840 ;
        RECT 3.990 91.440 295.600 92.840 ;
        RECT 3.990 72.440 296.000 91.440 ;
        RECT 3.990 71.040 295.600 72.440 ;
        RECT 3.990 55.440 296.000 71.040 ;
        RECT 4.400 54.040 296.000 55.440 ;
        RECT 3.990 48.640 296.000 54.040 ;
        RECT 3.990 47.240 295.600 48.640 ;
        RECT 3.990 18.040 296.000 47.240 ;
        RECT 4.400 16.640 296.000 18.040 ;
        RECT 3.990 10.715 296.000 16.640 ;
  END
END top_soc
END LIBRARY

